One B-rep face of a CAD part: STEP entity #1051.
In plain terms, the cylindrical face has radius 33 mm (diameter 66 mm), a partial arc.
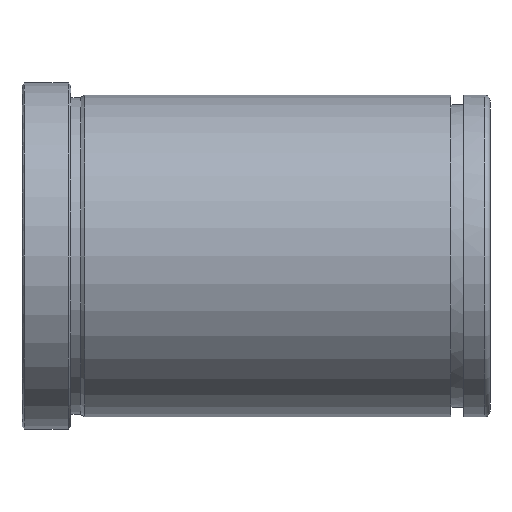
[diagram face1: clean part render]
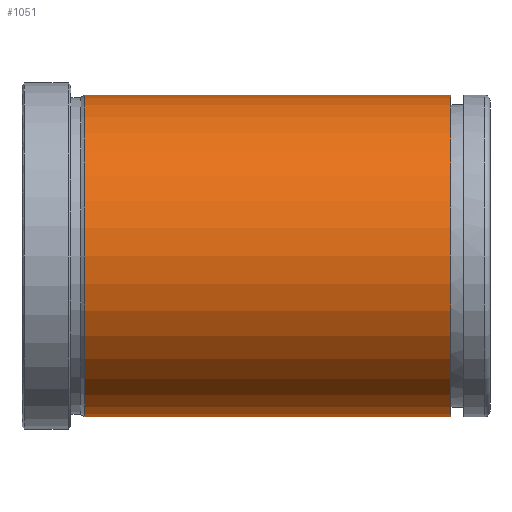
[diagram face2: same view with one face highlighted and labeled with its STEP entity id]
Its self-contained STEP definition (entity closure, numbers rounded to 3 decimals):
#851=CARTESIAN_POINT('Vertex',(12.866,0.,-33.)) ;
#858=CARTESIAN_POINT('Vertex',(12.866,0.,33.)) ;
#887=CARTESIAN_POINT('Axis2P3D Location',(12.866,0.,0.)) ;
#891=CARTESIAN_POINT('Vertex',(12.866,-33.,0.)) ;
#894=CARTESIAN_POINT('Axis2P3D Location',(12.866,0.,0.)) ;
#991=CARTESIAN_POINT('Line Origine',(192.,0.,33.)) ;
#995=CARTESIAN_POINT('Vertex',(88.,0.,33.)) ;
#1009=CARTESIAN_POINT('Vertex',(88.,0.,-33.)) ;
#1012=CARTESIAN_POINT('Line Origine',(192.,0.,-33.)) ;
#1026=CARTESIAN_POINT('Axis2P3D Location',(192.,0.,0.)) ;
#1031=CARTESIAN_POINT('Axis2P3D Location',(88.,0.,0.)) ;
#1035=CARTESIAN_POINT('Vertex',(88.,-33.,0.)) ;
#1038=CARTESIAN_POINT('Axis2P3D Location',(88.,0.,0.)) ;
#888=DIRECTION('Axis2P3D Direction',(1.,0.,-0.)) ;
#895=DIRECTION('Axis2P3D Direction',(1.,0.,-0.)) ;
#992=DIRECTION('Vector Direction',(-1.,0.,0.)) ;
#1013=DIRECTION('Vector Direction',(-1.,0.,0.)) ;
#1027=DIRECTION('Axis2P3D Direction',(-1.,-0.,-0.)) ;
#1028=DIRECTION('Axis2P3D XDirection',(0.,0.,-1.)) ;
#1032=DIRECTION('Axis2P3D Direction',(-1.,-0.,-0.)) ;
#1039=DIRECTION('Axis2P3D Direction',(-1.,-0.,-0.)) ;
#889=AXIS2_PLACEMENT_3D('Circle Axis2P3D',#887,#888,$) ;
#896=AXIS2_PLACEMENT_3D('Circle Axis2P3D',#894,#895,$) ;
#1029=AXIS2_PLACEMENT_3D('Cylinder Axis2P3D',#1026,#1027,#1028) ;
#1033=AXIS2_PLACEMENT_3D('Circle Axis2P3D',#1031,#1032,$) ;
#1040=AXIS2_PLACEMENT_3D('Circle Axis2P3D',#1038,#1039,$) ;
#1044=ORIENTED_EDGE('',*,*,#1016,.T.) ;
#1045=ORIENTED_EDGE('',*,*,#1037,.F.) ;
#1046=ORIENTED_EDGE('',*,*,#1042,.F.) ;
#1047=ORIENTED_EDGE('',*,*,#997,.T.) ;
#1048=ORIENTED_EDGE('',*,*,#898,.T.) ;
#1049=ORIENTED_EDGE('',*,*,#893,.T.) ;
#993=VECTOR('Line Direction',#992,1.) ;
#1014=VECTOR('Line Direction',#1013,1.) ;
#1051=ADVANCED_FACE('553-52X96',(#1050),#1030,.T.) ;
#890=CIRCLE('generated circle',#889,33.) ;
#897=CIRCLE('generated circle',#896,33.) ;
#1034=CIRCLE('generated circle',#1033,33.) ;
#1041=CIRCLE('generated circle',#1040,33.) ;
#1030=CYLINDRICAL_SURFACE('generated cylinder',#1029,33.) ;
#893=EDGE_CURVE('',#892,#852,#890,.T.) ;
#898=EDGE_CURVE('',#859,#892,#897,.T.) ;
#997=EDGE_CURVE('',#996,#859,#994,.T.) ;
#1016=EDGE_CURVE('',#852,#1010,#1015,.F.) ;
#1037=EDGE_CURVE('',#1036,#1010,#1034,.F.) ;
#1042=EDGE_CURVE('',#996,#1036,#1041,.F.) ;
#1043=EDGE_LOOP('',(#1044,#1045,#1046,#1047,#1048,#1049)) ;
#1050=FACE_OUTER_BOUND('',#1043,.T.) ;
#994=LINE('Line',#991,#993) ;
#1015=LINE('Line',#1012,#1014) ;
#852=VERTEX_POINT('',#851) ;
#859=VERTEX_POINT('',#858) ;
#892=VERTEX_POINT('',#891) ;
#996=VERTEX_POINT('',#995) ;
#1010=VERTEX_POINT('',#1009) ;
#1036=VERTEX_POINT('',#1035) ;
